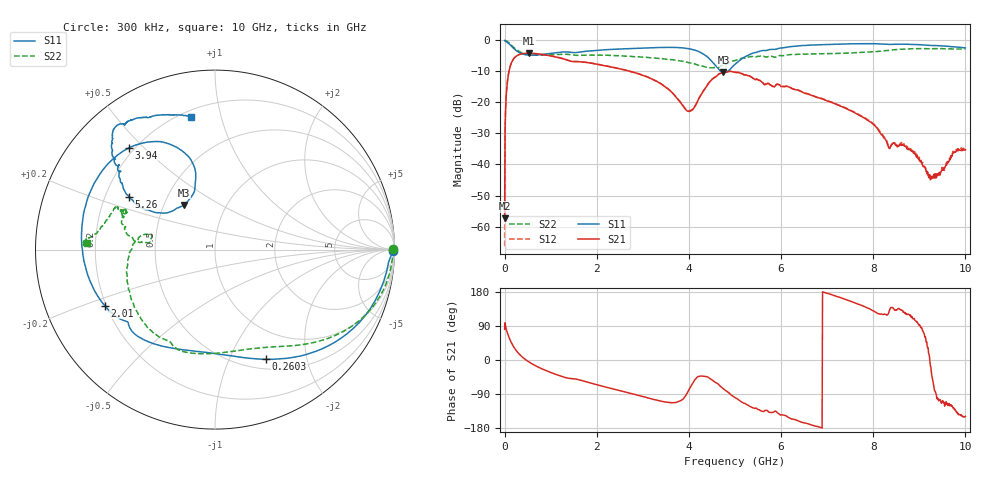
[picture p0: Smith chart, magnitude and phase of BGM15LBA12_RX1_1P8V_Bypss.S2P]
!Agilent Technologies,E5071C,MY46316587,B.13.01
!Date: Thu Dec 07 13:59:30 2017
!Data & Calibration Information:
!Freq	S11:SOLT2(ON)	S21:SOLT2(ON)	S12:SOLT2(ON)	S22:SOLT2(ON)
!PortZ  Port1:50+j0  Port2:50+j0
!Above PortZ is port z conversion or system Z0 setting when saving the data.
!When reading, reference impedance value at option line is always used.
# Hz S dB R 50
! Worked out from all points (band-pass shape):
!   1001 points, 300 kHz to 10 GHz, reference 50 ohm
!   highest |S21| = -4.18 dB at 520.3 MHz (marker M1); lowest = -57.3 dB at 300 kHz (marker M2)
!   |S21| within 3 dB of the highest: 151.2 MHz to 1.786 GHz (1.635 GHz wide, 169 % of centre)
!   lowest |S11| = -10.4 dB at 4.75 GHz (marker M3), VSWR 1.87, Z = 31.5 + j17.2 ohm
!   |S11| at or under -10 dB: 4.694 GHz to 4.833 GHz (139.6 MHz wide, 2.93 % of centre)
!   |S22| runs from -8.9 to -0.1 dB; largest |S21 - S12| = 0.0035
!   S11 on the Smith chart (normalised r, x): 300 kHz: open; 260.3 MHz: 0.62, -1.38; 2.01 GHz: 0.19, -0.23; 3.94 GHz: 0.18, +0.45; 5.26 GHz: 0.30, +0.26; 10 GHz: 0.24, +0.81
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300000  -0.07 -0.3  -57.29 81.0  -66.31 87.1  -0.07 0.0
6.02982e7  -0.67 -20.7  -13.47 71.7  -13.36 71.8  -0.41 -16.1
7.02979e7  -0.79 -23.9  -12.24 68.3  -12.18 68.1  -0.52 -18.5
1.402958e8  -1.80 -42.8  -7.58 47.4  -7.54 47.3  -1.48 -33.1
2.602922e8  -3.42 -65.0  -5.05 23.7  -5.02 23.5  -3.07 -49.4
5.202844e8  -4.78 -91.9  -4.18 -4.5  -4.17 -4.7  -4.60 -69.8
1.030269e9  -4.16 -121.0  -5.13 -34.3  -5.10 -34.5  -4.67 -96.6
1.67025e9  -3.74 -143.1  -6.96 -54.2  -6.91 -54.1  -4.84 -118.1
2.01024e9  -3.23 -153.1  -7.74 -65.6  -7.69 -65.5  -4.76 -126.4
3.3402e9  -2.34 159.5  -13.56 -107.0  -13.55 -106.6  -5.85 -163.8
3.940182e9  -2.58 130.4  -22.49 -91.9  -22.39 -91.9  -7.00 174.4
4.090177e9  -3.01 122.1  -22.18 -59.6  -22.07 -59.4  -7.45 170.0
4.450166e9  -6.06 104.5  -13.41 -48.4  -13.42 -48.4  -8.87 168.9
4.750158e9  -10.36 125.1  -10.36 -76.5  -10.36 -76.6  -7.93 174.4
5.00015e9  -7.72 148.8  -10.31 -99.1  -10.28 -99.1  -6.55 171.5
5.260142e9  -4.99 148.4  -11.31 -118.1  -11.28 -118.3  -5.53 165.1
6.6701e9  -1.55 133.1  -17.79 -171.6  -17.67 -171.5  -4.40 157.0
7.920062e9  -1.10 128.2  -26.14 135.3  -25.93 135.2  -3.75 169.2
8.34005e9  -1.34 125.9  -34.75 126.0  -34.48 126.4  -3.27 173.8
8.860034e9  -1.36 121.7  -35.62 108.9  -35.61 108.4  -2.75 176.2
9.260022e9  -1.69 116.7  -44.52 -30.9  -44.60 -32.8  -2.77 177.0
1e10  -2.48 100.2  -35.31 -148.8  -34.77 -152.7  -2.89 176.9
